# Generated by FakeRAM 2.0
VERSION 5.7 ;
BUSBITCHARS "[]" ;
PROPERTYDEFINITIONS
  MACRO width INTEGER ;
  MACRO depth INTEGER ;
  MACRO banks INTEGER ;
END PROPERTYDEFINITIONS
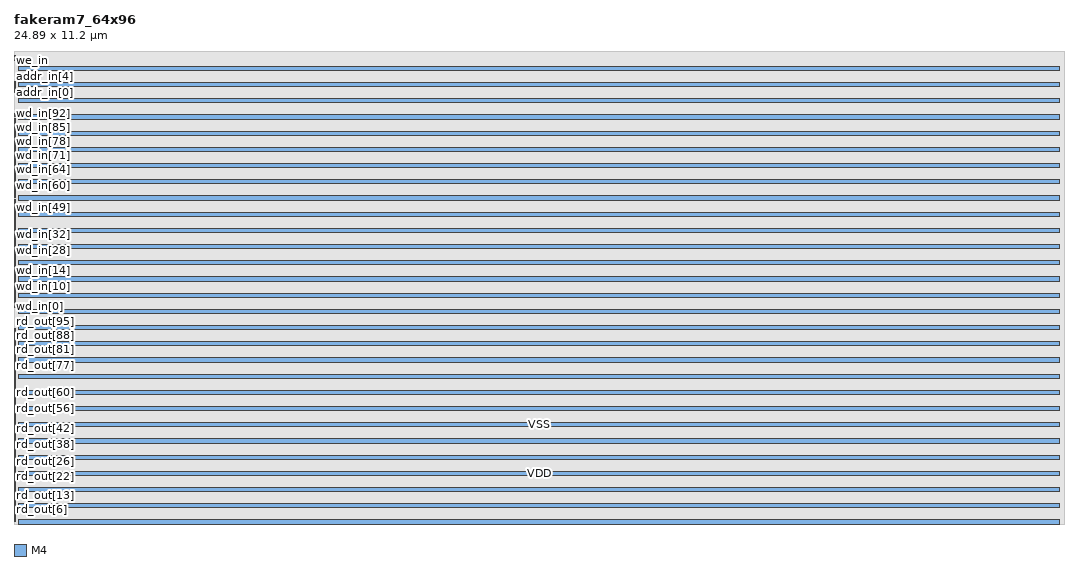
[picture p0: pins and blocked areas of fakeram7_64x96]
MACRO fakeram7_64x96
  PROPERTY width 96 ;
  PROPERTY depth 64 ;
  PROPERTY banks 2 ;
  FOREIGN fakeram7_64x96 0 0 ;
  SYMMETRY X Y R90 ;
  SIZE 24.8900 BY 11.2000 ;
  CLASS BLOCK ;
  PIN rd_out[0]
    DIRECTION OUTPUT ;
    USE SIGNAL ;
    PORT
      LAYER M4 ;
      RECT 0.00000 0.04800 0.03600 0.07200 ;
    END
  END rd_out[0]
  PIN rd_out[1]
    DIRECTION OUTPUT ;
    USE SIGNAL ;
    PORT
      LAYER M4 ;
      RECT 0.00000 0.09600 0.03600 0.12000 ;
    END
  END rd_out[1]
  PIN rd_out[2]
    DIRECTION OUTPUT ;
    USE SIGNAL ;
    PORT
      LAYER M4 ;
      RECT 0.00000 0.14400 0.03600 0.16800 ;
    END
  END rd_out[2]
  PIN rd_out[3]
    DIRECTION OUTPUT ;
    USE SIGNAL ;
    PORT
      LAYER M4 ;
      RECT 0.00000 0.19200 0.03600 0.21600 ;
    END
  END rd_out[3]
  PIN rd_out[4]
    DIRECTION OUTPUT ;
    USE SIGNAL ;
    PORT
      LAYER M4 ;
      RECT 0.00000 0.24000 0.03600 0.26400 ;
    END
  END rd_out[4]
  PIN rd_out[5]
    DIRECTION OUTPUT ;
    USE SIGNAL ;
    PORT
      LAYER M4 ;
      RECT 0.00000 0.28800 0.03600 0.31200 ;
    END
  END rd_out[5]
  PIN rd_out[6]
    DIRECTION OUTPUT ;
    USE SIGNAL ;
    PORT
      LAYER M4 ;
      RECT 0.00000 0.33600 0.03600 0.36000 ;
    END
  END rd_out[6]
  PIN rd_out[7]
    DIRECTION OUTPUT ;
    USE SIGNAL ;
    PORT
      LAYER M4 ;
      RECT 0.00000 0.38400 0.03600 0.40800 ;
    END
  END rd_out[7]
  PIN rd_out[8]
    DIRECTION OUTPUT ;
    USE SIGNAL ;
    PORT
      LAYER M4 ;
      RECT 0.00000 0.43200 0.03600 0.45600 ;
    END
  END rd_out[8]
  PIN rd_out[9]
    DIRECTION OUTPUT ;
    USE SIGNAL ;
    PORT
      LAYER M4 ;
      RECT 0.00000 0.48000 0.03600 0.50400 ;
    END
  END rd_out[9]
  PIN rd_out[10]
    DIRECTION OUTPUT ;
    USE SIGNAL ;
    PORT
      LAYER M4 ;
      RECT 0.00000 0.52800 0.03600 0.55200 ;
    END
  END rd_out[10]
  PIN rd_out[11]
    DIRECTION OUTPUT ;
    USE SIGNAL ;
    PORT
      LAYER M4 ;
      RECT 0.00000 0.57600 0.03600 0.60000 ;
    END
  END rd_out[11]
  PIN rd_out[12]
    DIRECTION OUTPUT ;
    USE SIGNAL ;
    PORT
      LAYER M4 ;
      RECT 0.00000 0.62400 0.03600 0.64800 ;
    END
  END rd_out[12]
  PIN rd_out[13]
    DIRECTION OUTPUT ;
    USE SIGNAL ;
    PORT
      LAYER M4 ;
      RECT 0.00000 0.67200 0.03600 0.69600 ;
    END
  END rd_out[13]
  PIN rd_out[14]
    DIRECTION OUTPUT ;
    USE SIGNAL ;
    PORT
      LAYER M4 ;
      RECT 0.00000 0.72000 0.03600 0.74400 ;
    END
  END rd_out[14]
  PIN rd_out[15]
    DIRECTION OUTPUT ;
    USE SIGNAL ;
    PORT
      LAYER M4 ;
      RECT 0.00000 0.76800 0.03600 0.79200 ;
    END
  END rd_out[15]
  PIN rd_out[16]
    DIRECTION OUTPUT ;
    USE SIGNAL ;
    PORT
      LAYER M4 ;
      RECT 0.00000 0.81600 0.03600 0.84000 ;
    END
  END rd_out[16]
  PIN rd_out[17]
    DIRECTION OUTPUT ;
    USE SIGNAL ;
    PORT
      LAYER M4 ;
      RECT 0.00000 0.86400 0.03600 0.88800 ;
    END
  END rd_out[17]
  PIN rd_out[18]
    DIRECTION OUTPUT ;
    USE SIGNAL ;
    PORT
      LAYER M4 ;
      RECT 0.00000 0.91200 0.03600 0.93600 ;
    END
  END rd_out[18]
  PIN rd_out[19]
    DIRECTION OUTPUT ;
    USE SIGNAL ;
    PORT
      LAYER M4 ;
      RECT 0.00000 0.96000 0.03600 0.98400 ;
    END
  END rd_out[19]
  PIN rd_out[20]
    DIRECTION OUTPUT ;
    USE SIGNAL ;
    PORT
      LAYER M4 ;
      RECT 0.00000 1.00800 0.03600 1.03200 ;
    END
  END rd_out[20]
  PIN rd_out[21]
    DIRECTION OUTPUT ;
    USE SIGNAL ;
    PORT
      LAYER M4 ;
      RECT 0.00000 1.05600 0.03600 1.08000 ;
    END
  END rd_out[21]
  PIN rd_out[22]
    DIRECTION OUTPUT ;
    USE SIGNAL ;
    PORT
      LAYER M4 ;
      RECT 0.00000 1.10400 0.03600 1.12800 ;
    END
  END rd_out[22]
  PIN rd_out[23]
    DIRECTION OUTPUT ;
    USE SIGNAL ;
    PORT
      LAYER M4 ;
      RECT 0.00000 1.15200 0.03600 1.17600 ;
    END
  END rd_out[23]
  PIN rd_out[24]
    DIRECTION OUTPUT ;
    USE SIGNAL ;
    PORT
      LAYER M4 ;
      RECT 0.00000 1.20000 0.03600 1.22400 ;
    END
  END rd_out[24]
  PIN rd_out[25]
    DIRECTION OUTPUT ;
    USE SIGNAL ;
    PORT
      LAYER M4 ;
      RECT 0.00000 1.24800 0.03600 1.27200 ;
    END
  END rd_out[25]
  PIN rd_out[26]
    DIRECTION OUTPUT ;
    USE SIGNAL ;
    PORT
      LAYER M4 ;
      RECT 0.00000 1.29600 0.03600 1.32000 ;
    END
  END rd_out[26]
  PIN rd_out[27]
    DIRECTION OUTPUT ;
    USE SIGNAL ;
    PORT
      LAYER M4 ;
      RECT 0.00000 1.34400 0.03600 1.36800 ;
    END
  END rd_out[27]
  PIN rd_out[28]
    DIRECTION OUTPUT ;
    USE SIGNAL ;
    PORT
      LAYER M4 ;
      RECT 0.00000 1.39200 0.03600 1.41600 ;
    END
  END rd_out[28]
  PIN rd_out[29]
    DIRECTION OUTPUT ;
    USE SIGNAL ;
    PORT
      LAYER M4 ;
      RECT 0.00000 1.44000 0.03600 1.46400 ;
    END
  END rd_out[29]
  PIN rd_out[30]
    DIRECTION OUTPUT ;
    USE SIGNAL ;
    PORT
      LAYER M4 ;
      RECT 0.00000 1.48800 0.03600 1.51200 ;
    END
  END rd_out[30]
  PIN rd_out[31]
    DIRECTION OUTPUT ;
    USE SIGNAL ;
    PORT
      LAYER M4 ;
      RECT 0.00000 1.53600 0.03600 1.56000 ;
    END
  END rd_out[31]
  PIN rd_out[32]
    DIRECTION OUTPUT ;
    USE SIGNAL ;
    PORT
      LAYER M4 ;
      RECT 0.00000 1.58400 0.03600 1.60800 ;
    END
  END rd_out[32]
  PIN rd_out[33]
    DIRECTION OUTPUT ;
    USE SIGNAL ;
    PORT
      LAYER M4 ;
      RECT 0.00000 1.63200 0.03600 1.65600 ;
    END
  END rd_out[33]
  PIN rd_out[34]
    DIRECTION OUTPUT ;
    USE SIGNAL ;
    PORT
      LAYER M4 ;
      RECT 0.00000 1.68000 0.03600 1.70400 ;
    END
  END rd_out[34]
  PIN rd_out[35]
    DIRECTION OUTPUT ;
    USE SIGNAL ;
    PORT
      LAYER M4 ;
      RECT 0.00000 1.72800 0.03600 1.75200 ;
    END
  END rd_out[35]
  PIN rd_out[36]
    DIRECTION OUTPUT ;
    USE SIGNAL ;
    PORT
      LAYER M4 ;
      RECT 0.00000 1.77600 0.03600 1.80000 ;
    END
  END rd_out[36]
  PIN rd_out[37]
    DIRECTION OUTPUT ;
    USE SIGNAL ;
    PORT
      LAYER M4 ;
      RECT 0.00000 1.82400 0.03600 1.84800 ;
    END
  END rd_out[37]
  PIN rd_out[38]
    DIRECTION OUTPUT ;
    USE SIGNAL ;
    PORT
      LAYER M4 ;
      RECT 0.00000 1.87200 0.03600 1.89600 ;
    END
  END rd_out[38]
  PIN rd_out[39]
    DIRECTION OUTPUT ;
    USE SIGNAL ;
    PORT
      LAYER M4 ;
      RECT 0.00000 1.92000 0.03600 1.94400 ;
    END
  END rd_out[39]
  PIN rd_out[40]
    DIRECTION OUTPUT ;
    USE SIGNAL ;
    PORT
      LAYER M4 ;
      RECT 0.00000 1.96800 0.03600 1.99200 ;
    END
  END rd_out[40]
  PIN rd_out[41]
    DIRECTION OUTPUT ;
    USE SIGNAL ;
    PORT
      LAYER M4 ;
      RECT 0.00000 2.01600 0.03600 2.04000 ;
    END
  END rd_out[41]
  PIN rd_out[42]
    DIRECTION OUTPUT ;
    USE SIGNAL ;
    PORT
      LAYER M4 ;
      RECT 0.00000 2.06400 0.03600 2.08800 ;
    END
  END rd_out[42]
  PIN rd_out[43]
    DIRECTION OUTPUT ;
    USE SIGNAL ;
    PORT
      LAYER M4 ;
      RECT 0.00000 2.11200 0.03600 2.13600 ;
    END
  END rd_out[43]
  PIN rd_out[44]
    DIRECTION OUTPUT ;
    USE SIGNAL ;
    PORT
      LAYER M4 ;
      RECT 0.00000 2.16000 0.03600 2.18400 ;
    END
  END rd_out[44]
  PIN rd_out[45]
    DIRECTION OUTPUT ;
    USE SIGNAL ;
    PORT
      LAYER M4 ;
      RECT 0.00000 2.20800 0.03600 2.23200 ;
    END
  END rd_out[45]
  PIN rd_out[46]
    DIRECTION OUTPUT ;
    USE SIGNAL ;
    PORT
      LAYER M4 ;
      RECT 0.00000 2.25600 0.03600 2.28000 ;
    END
  END rd_out[46]
  PIN rd_out[47]
    DIRECTION OUTPUT ;
    USE SIGNAL ;
    PORT
      LAYER M4 ;
      RECT 0.00000 2.30400 0.03600 2.32800 ;
    END
  END rd_out[47]
  PIN rd_out[48]
    DIRECTION OUTPUT ;
    USE SIGNAL ;
    PORT
      LAYER M4 ;
      RECT 0.00000 2.35200 0.03600 2.37600 ;
    END
  END rd_out[48]
  PIN rd_out[49]
    DIRECTION OUTPUT ;
    USE SIGNAL ;
    PORT
      LAYER M4 ;
      RECT 0.00000 2.40000 0.03600 2.42400 ;
    END
  END rd_out[49]
  PIN rd_out[50]
    DIRECTION OUTPUT ;
    USE SIGNAL ;
    PORT
      LAYER M4 ;
      RECT 0.00000 2.44800 0.03600 2.47200 ;
    END
  END rd_out[50]
  PIN rd_out[51]
    DIRECTION OUTPUT ;
    USE SIGNAL ;
    PORT
      LAYER M4 ;
      RECT 0.00000 2.49600 0.03600 2.52000 ;
    END
  END rd_out[51]
  PIN rd_out[52]
    DIRECTION OUTPUT ;
    USE SIGNAL ;
    PORT
      LAYER M4 ;
      RECT 0.00000 2.54400 0.03600 2.56800 ;
    END
  END rd_out[52]
  PIN rd_out[53]
    DIRECTION OUTPUT ;
    USE SIGNAL ;
    PORT
      LAYER M4 ;
      RECT 0.00000 2.59200 0.03600 2.61600 ;
    END
  END rd_out[53]
  PIN rd_out[54]
    DIRECTION OUTPUT ;
    USE SIGNAL ;
    PORT
      LAYER M4 ;
      RECT 0.00000 2.64000 0.03600 2.66400 ;
    END
  END rd_out[54]
  PIN rd_out[55]
    DIRECTION OUTPUT ;
    USE SIGNAL ;
    PORT
      LAYER M4 ;
      RECT 0.00000 2.68800 0.03600 2.71200 ;
    END
  END rd_out[55]
  PIN rd_out[56]
    DIRECTION OUTPUT ;
    USE SIGNAL ;
    PORT
      LAYER M4 ;
      RECT 0.00000 2.73600 0.03600 2.76000 ;
    END
  END rd_out[56]
  PIN rd_out[57]
    DIRECTION OUTPUT ;
    USE SIGNAL ;
    PORT
      LAYER M4 ;
      RECT 0.00000 2.78400 0.03600 2.80800 ;
    END
  END rd_out[57]
  PIN rd_out[58]
    DIRECTION OUTPUT ;
    USE SIGNAL ;
    PORT
      LAYER M4 ;
      RECT 0.00000 2.83200 0.03600 2.85600 ;
    END
  END rd_out[58]
  PIN rd_out[59]
    DIRECTION OUTPUT ;
    USE SIGNAL ;
    PORT
      LAYER M4 ;
      RECT 0.00000 2.88000 0.03600 2.90400 ;
    END
  END rd_out[59]
  PIN rd_out[60]
    DIRECTION OUTPUT ;
    USE SIGNAL ;
    PORT
      LAYER M4 ;
      RECT 0.00000 2.92800 0.03600 2.95200 ;
    END
  END rd_out[60]
  PIN rd_out[61]
    DIRECTION OUTPUT ;
    USE SIGNAL ;
    PORT
      LAYER M4 ;
      RECT 0.00000 2.97600 0.03600 3.00000 ;
    END
  END rd_out[61]
  PIN rd_out[62]
    DIRECTION OUTPUT ;
    USE SIGNAL ;
    PORT
      LAYER M4 ;
      RECT 0.00000 3.02400 0.03600 3.04800 ;
    END
  END rd_out[62]
  PIN rd_out[63]
    DIRECTION OUTPUT ;
    USE SIGNAL ;
    PORT
      LAYER M4 ;
      RECT 0.00000 3.07200 0.03600 3.09600 ;
    END
  END rd_out[63]
  PIN rd_out[64]
    DIRECTION OUTPUT ;
    USE SIGNAL ;
    PORT
      LAYER M4 ;
      RECT 0.00000 3.12000 0.03600 3.14400 ;
    END
  END rd_out[64]
  PIN rd_out[65]
    DIRECTION OUTPUT ;
    USE SIGNAL ;
    PORT
      LAYER M4 ;
      RECT 0.00000 3.16800 0.03600 3.19200 ;
    END
  END rd_out[65]
  PIN rd_out[66]
    DIRECTION OUTPUT ;
    USE SIGNAL ;
    PORT
      LAYER M4 ;
      RECT 0.00000 3.21600 0.03600 3.24000 ;
    END
  END rd_out[66]
  PIN rd_out[67]
    DIRECTION OUTPUT ;
    USE SIGNAL ;
    PORT
      LAYER M4 ;
      RECT 0.00000 3.26400 0.03600 3.28800 ;
    END
  END rd_out[67]
  PIN rd_out[68]
    DIRECTION OUTPUT ;
    USE SIGNAL ;
    PORT
      LAYER M4 ;
      RECT 0.00000 3.31200 0.03600 3.33600 ;
    END
  END rd_out[68]
  PIN rd_out[69]
    DIRECTION OUTPUT ;
    USE SIGNAL ;
    PORT
      LAYER M4 ;
      RECT 0.00000 3.36000 0.03600 3.38400 ;
    END
  END rd_out[69]
  PIN rd_out[70]
    DIRECTION OUTPUT ;
    USE SIGNAL ;
    PORT
      LAYER M4 ;
      RECT 0.00000 3.40800 0.03600 3.43200 ;
    END
  END rd_out[70]
  PIN rd_out[71]
    DIRECTION OUTPUT ;
    USE SIGNAL ;
    PORT
      LAYER M4 ;
      RECT 0.00000 3.45600 0.03600 3.48000 ;
    END
  END rd_out[71]
  PIN rd_out[72]
    DIRECTION OUTPUT ;
    USE SIGNAL ;
    PORT
      LAYER M4 ;
      RECT 0.00000 3.50400 0.03600 3.52800 ;
    END
  END rd_out[72]
  PIN rd_out[73]
    DIRECTION OUTPUT ;
    USE SIGNAL ;
    PORT
      LAYER M4 ;
      RECT 0.00000 3.55200 0.03600 3.57600 ;
    END
  END rd_out[73]
  PIN rd_out[74]
    DIRECTION OUTPUT ;
    USE SIGNAL ;
    PORT
      LAYER M4 ;
      RECT 0.00000 3.60000 0.03600 3.62400 ;
    END
  END rd_out[74]
  PIN rd_out[75]
    DIRECTION OUTPUT ;
    USE SIGNAL ;
    PORT
      LAYER M4 ;
      RECT 0.00000 3.64800 0.03600 3.67200 ;
    END
  END rd_out[75]
  PIN rd_out[76]
    DIRECTION OUTPUT ;
    USE SIGNAL ;
    PORT
      LAYER M4 ;
      RECT 0.00000 3.69600 0.03600 3.72000 ;
    END
  END rd_out[76]
  PIN rd_out[77]
    DIRECTION OUTPUT ;
    USE SIGNAL ;
    PORT
      LAYER M4 ;
      RECT 0.00000 3.74400 0.03600 3.76800 ;
    END
  END rd_out[77]
  PIN rd_out[78]
    DIRECTION OUTPUT ;
    USE SIGNAL ;
    PORT
      LAYER M4 ;
      RECT 0.00000 3.79200 0.03600 3.81600 ;
    END
  END rd_out[78]
  PIN rd_out[79]
    DIRECTION OUTPUT ;
    USE SIGNAL ;
    PORT
      LAYER M4 ;
      RECT 0.00000 3.84000 0.03600 3.86400 ;
    END
  END rd_out[79]
  PIN rd_out[80]
    DIRECTION OUTPUT ;
    USE SIGNAL ;
    PORT
      LAYER M4 ;
      RECT 0.00000 3.88800 0.03600 3.91200 ;
    END
  END rd_out[80]
  PIN rd_out[81]
    DIRECTION OUTPUT ;
    USE SIGNAL ;
    PORT
      LAYER M4 ;
      RECT 0.00000 3.93600 0.03600 3.96000 ;
    END
  END rd_out[81]
  PIN rd_out[82]
    DIRECTION OUTPUT ;
    USE SIGNAL ;
    PORT
      LAYER M4 ;
      RECT 0.00000 3.98400 0.03600 4.00800 ;
    END
  END rd_out[82]
  PIN rd_out[83]
    DIRECTION OUTPUT ;
    USE SIGNAL ;
    PORT
      LAYER M4 ;
      RECT 0.00000 4.03200 0.03600 4.05600 ;
    END
  END rd_out[83]
  PIN rd_out[84]
    DIRECTION OUTPUT ;
    USE SIGNAL ;
    PORT
      LAYER M4 ;
      RECT 0.00000 4.08000 0.03600 4.10400 ;
    END
  END rd_out[84]
  PIN rd_out[85]
    DIRECTION OUTPUT ;
    USE SIGNAL ;
    PORT
      LAYER M4 ;
      RECT 0.00000 4.12800 0.03600 4.15200 ;
    END
  END rd_out[85]
  PIN rd_out[86]
    DIRECTION OUTPUT ;
    USE SIGNAL ;
    PORT
      LAYER M4 ;
      RECT 0.00000 4.17600 0.03600 4.20000 ;
    END
  END rd_out[86]
  PIN rd_out[87]
    DIRECTION OUTPUT ;
    USE SIGNAL ;
    PORT
      LAYER M4 ;
      RECT 0.00000 4.22400 0.03600 4.24800 ;
    END
  END rd_out[87]
  PIN rd_out[88]
    DIRECTION OUTPUT ;
    USE SIGNAL ;
    PORT
      LAYER M4 ;
      RECT 0.00000 4.27200 0.03600 4.29600 ;
    END
  END rd_out[88]
  PIN rd_out[89]
    DIRECTION OUTPUT ;
    USE SIGNAL ;
    PORT
      LAYER M4 ;
      RECT 0.00000 4.32000 0.03600 4.34400 ;
    END
  END rd_out[89]
  PIN rd_out[90]
    DIRECTION OUTPUT ;
    USE SIGNAL ;
    PORT
      LAYER M4 ;
      RECT 0.00000 4.36800 0.03600 4.39200 ;
    END
  END rd_out[90]
  PIN rd_out[91]
    DIRECTION OUTPUT ;
    USE SIGNAL ;
    PORT
      LAYER M4 ;
      RECT 0.00000 4.41600 0.03600 4.44000 ;
    END
  END rd_out[91]
  PIN rd_out[92]
    DIRECTION OUTPUT ;
    USE SIGNAL ;
    PORT
      LAYER M4 ;
      RECT 0.00000 4.46400 0.03600 4.48800 ;
    END
  END rd_out[92]
  PIN rd_out[93]
    DIRECTION OUTPUT ;
    USE SIGNAL ;
    PORT
      LAYER M4 ;
      RECT 0.00000 4.51200 0.03600 4.53600 ;
    END
  END rd_out[93]
  PIN rd_out[94]
    DIRECTION OUTPUT ;
    USE SIGNAL ;
    PORT
      LAYER M4 ;
      RECT 0.00000 4.56000 0.03600 4.58400 ;
    END
  END rd_out[94]
  PIN rd_out[95]
    DIRECTION OUTPUT ;
    USE SIGNAL ;
    PORT
      LAYER M4 ;
      RECT 0.00000 4.60800 0.03600 4.63200 ;
    END
  END rd_out[95]
  PIN wd_in[0]
    DIRECTION INPUT ;
    USE SIGNAL ;
    PORT
      LAYER M4 ;
      RECT 0.00000 5.13600 0.03600 5.16000 ;
    END
  END wd_in[0]
  PIN wd_in[1]
    DIRECTION INPUT ;
    USE SIGNAL ;
    PORT
      LAYER M4 ;
      RECT 0.00000 5.18400 0.03600 5.20800 ;
    END
  END wd_in[1]
  PIN wd_in[2]
    DIRECTION INPUT ;
    USE SIGNAL ;
    PORT
      LAYER M4 ;
      RECT 0.00000 5.23200 0.03600 5.25600 ;
    END
  END wd_in[2]
  PIN wd_in[3]
    DIRECTION INPUT ;
    USE SIGNAL ;
    PORT
      LAYER M4 ;
      RECT 0.00000 5.28000 0.03600 5.30400 ;
    END
  END wd_in[3]
  PIN wd_in[4]
    DIRECTION INPUT ;
    USE SIGNAL ;
    PORT
      LAYER M4 ;
      RECT 0.00000 5.32800 0.03600 5.35200 ;
    END
  END wd_in[4]
  PIN wd_in[5]
    DIRECTION INPUT ;
    USE SIGNAL ;
    PORT
      LAYER M4 ;
      RECT 0.00000 5.37600 0.03600 5.40000 ;
    END
  END wd_in[5]
  PIN wd_in[6]
    DIRECTION INPUT ;
    USE SIGNAL ;
    PORT
      LAYER M4 ;
      RECT 0.00000 5.42400 0.03600 5.44800 ;
    END
  END wd_in[6]
  PIN wd_in[7]
    DIRECTION INPUT ;
    USE SIGNAL ;
    PORT
      LAYER M4 ;
      RECT 0.00000 5.47200 0.03600 5.49600 ;
    END
  END wd_in[7]
  PIN wd_in[8]
    DIRECTION INPUT ;
    USE SIGNAL ;
    PORT
      LAYER M4 ;
      RECT 0.00000 5.52000 0.03600 5.54400 ;
    END
  END wd_in[8]
  PIN wd_in[9]
    DIRECTION INPUT ;
    USE SIGNAL ;
    PORT
      LAYER M4 ;
      RECT 0.00000 5.56800 0.03600 5.59200 ;
    END
  END wd_in[9]
  PIN wd_in[10]
    DIRECTION INPUT ;
    USE SIGNAL ;
    PORT
      LAYER M4 ;
      RECT 0.00000 5.61600 0.03600 5.64000 ;
    END
  END wd_in[10]
  PIN wd_in[11]
    DIRECTION INPUT ;
    USE SIGNAL ;
    PORT
      LAYER M4 ;
      RECT 0.00000 5.66400 0.03600 5.68800 ;
    END
  END wd_in[11]
  PIN wd_in[12]
    DIRECTION INPUT ;
    USE SIGNAL ;
    PORT
      LAYER M4 ;
      RECT 0.00000 5.71200 0.03600 5.73600 ;
    END
  END wd_in[12]
  PIN wd_in[13]
    DIRECTION INPUT ;
    USE SIGNAL ;
    PORT
      LAYER M4 ;
      RECT 0.00000 5.76000 0.03600 5.78400 ;
    END
  END wd_in[13]
  PIN wd_in[14]
    DIRECTION INPUT ;
    USE SIGNAL ;
    PORT
      LAYER M4 ;
      RECT 0.00000 5.80800 0.03600 5.83200 ;
    END
  END wd_in[14]
  PIN wd_in[15]
    DIRECTION INPUT ;
    USE SIGNAL ;
    PORT
      LAYER M4 ;
      RECT 0.00000 5.85600 0.03600 5.88000 ;
    END
  END wd_in[15]
  PIN wd_in[16]
    DIRECTION INPUT ;
    USE SIGNAL ;
    PORT
      LAYER M4 ;
      RECT 0.00000 5.90400 0.03600 5.92800 ;
    END
  END wd_in[16]
  PIN wd_in[17]
    DIRECTION INPUT ;
    USE SIGNAL ;
    PORT
      LAYER M4 ;
      RECT 0.00000 5.95200 0.03600 5.97600 ;
    END
  END wd_in[17]
  PIN wd_in[18]
    DIRECTION INPUT ;
    USE SIGNAL ;
    PORT
      LAYER M4 ;
      RECT 0.00000 6.00000 0.03600 6.02400 ;
    END
  END wd_in[18]
  PIN wd_in[19]
    DIRECTION INPUT ;
    USE SIGNAL ;
    PORT
      LAYER M4 ;
      RECT 0.00000 6.04800 0.03600 6.07200 ;
    END
  END wd_in[19]
  PIN wd_in[20]
    DIRECTION INPUT ;
    USE SIGNAL ;
    PORT
      LAYER M4 ;
      RECT 0.00000 6.09600 0.03600 6.12000 ;
    END
  END wd_in[20]
  PIN wd_in[21]
    DIRECTION INPUT ;
    USE SIGNAL ;
    PORT
      LAYER M4 ;
      RECT 0.00000 6.14400 0.03600 6.16800 ;
    END
  END wd_in[21]
  PIN wd_in[22]
    DIRECTION INPUT ;
    USE SIGNAL ;
    PORT
      LAYER M4 ;
      RECT 0.00000 6.19200 0.03600 6.21600 ;
    END
  END wd_in[22]
  PIN wd_in[23]
    DIRECTION INPUT ;
    USE SIGNAL ;
    PORT
      LAYER M4 ;
      RECT 0.00000 6.24000 0.03600 6.26400 ;
    END
  END wd_in[23]
  PIN wd_in[24]
    DIRECTION INPUT ;
    USE SIGNAL ;
    PORT
      LAYER M4 ;
      RECT 0.00000 6.28800 0.03600 6.31200 ;
    END
  END wd_in[24]
  PIN wd_in[25]
    DIRECTION INPUT ;
    USE SIGNAL ;
    PORT
      LAYER M4 ;
      RECT 0.00000 6.33600 0.03600 6.36000 ;
    END
  END wd_in[25]
  PIN wd_in[26]
    DIRECTION INPUT ;
    USE SIGNAL ;
    PORT
      LAYER M4 ;
      RECT 0.00000 6.38400 0.03600 6.40800 ;
    END
  END wd_in[26]
  PIN wd_in[27]
    DIRECTION INPUT ;
    USE SIGNAL ;
    PORT
      LAYER M4 ;
      RECT 0.00000 6.43200 0.03600 6.45600 ;
    END
  END wd_in[27]
  PIN wd_in[28]
    DIRECTION INPUT ;
    USE SIGNAL ;
    PORT
      LAYER M4 ;
      RECT 0.00000 6.48000 0.03600 6.50400 ;
    END
  END wd_in[28]
  PIN wd_in[29]
    DIRECTION INPUT ;
    USE SIGNAL ;
    PORT
      LAYER M4 ;
      RECT 0.00000 6.52800 0.03600 6.55200 ;
    END
  END wd_in[29]
  PIN wd_in[30]
    DIRECTION INPUT ;
    USE SIGNAL ;
    PORT
      LAYER M4 ;
      RECT 0.00000 6.57600 0.03600 6.60000 ;
    END
  END wd_in[30]
  PIN wd_in[31]
    DIRECTION INPUT ;
    USE SIGNAL ;
    PORT
      LAYER M4 ;
      RECT 0.00000 6.62400 0.03600 6.64800 ;
    END
  END wd_in[31]
  PIN wd_in[32]
    DIRECTION INPUT ;
    USE SIGNAL ;
    PORT
      LAYER M4 ;
      RECT 0.00000 6.67200 0.03600 6.69600 ;
    END
  END wd_in[32]
  PIN wd_in[33]
    DIRECTION INPUT ;
    USE SIGNAL ;
    PORT
      LAYER M4 ;
      RECT 0.00000 6.72000 0.03600 6.74400 ;
    END
  END wd_in[33]
  PIN wd_in[34]
    DIRECTION INPUT ;
    USE SIGNAL ;
    PORT
      LAYER M4 ;
      RECT 0.00000 6.76800 0.03600 6.79200 ;
    END
  END wd_in[34]
  PIN wd_in[35]
    DIRECTION INPUT ;
    USE SIGNAL ;
    PORT
      LAYER M4 ;
      RECT 0.00000 6.81600 0.03600 6.84000 ;
    END
  END wd_in[35]
  PIN wd_in[36]
    DIRECTION INPUT ;
    USE SIGNAL ;
    PORT
      LAYER M4 ;
      RECT 0.00000 6.86400 0.03600 6.88800 ;
    END
  END wd_in[36]
  PIN wd_in[37]
    DIRECTION INPUT ;
    USE SIGNAL ;
    PORT
      LAYER M4 ;
      RECT 0.00000 6.91200 0.03600 6.93600 ;
    END
  END wd_in[37]
  PIN wd_in[38]
    DIRECTION INPUT ;
    USE SIGNAL ;
    PORT
      LAYER M4 ;
      RECT 0.00000 6.96000 0.03600 6.98400 ;
    END
  END wd_in[38]
  PIN wd_in[39]
    DIRECTION INPUT ;
    USE SIGNAL ;
    PORT
      LAYER M4 ;
      RECT 0.00000 7.00800 0.03600 7.03200 ;
    END
  END wd_in[39]
  PIN wd_in[40]
    DIRECTION INPUT ;
    USE SIGNAL ;
    PORT
      LAYER M4 ;
      RECT 0.00000 7.05600 0.03600 7.08000 ;
    END
  END wd_in[40]
  PIN wd_in[41]
    DIRECTION INPUT ;
    USE SIGNAL ;
    PORT
      LAYER M4 ;
      RECT 0.00000 7.10400 0.03600 7.12800 ;
    END
  END wd_in[41]
  PIN wd_in[42]
    DIRECTION INPUT ;
    USE SIGNAL ;
    PORT
      LAYER M4 ;
      RECT 0.00000 7.15200 0.03600 7.17600 ;
    END
  END wd_in[42]
  PIN wd_in[43]
    DIRECTION INPUT ;
    USE SIGNAL ;
    PORT
      LAYER M4 ;
      RECT 0.00000 7.20000 0.03600 7.22400 ;
    END
  END wd_in[43]
  PIN wd_in[44]
    DIRECTION INPUT ;
    USE SIGNAL ;
    PORT
      LAYER M4 ;
      RECT 0.00000 7.24800 0.03600 7.27200 ;
    END
  END wd_in[44]
  PIN wd_in[45]
    DIRECTION INPUT ;
    USE SIGNAL ;
    PORT
      LAYER M4 ;
      RECT 0.00000 7.29600 0.03600 7.32000 ;
    END
  END wd_in[45]
  PIN wd_in[46]
    DIRECTION INPUT ;
    USE SIGNAL ;
    PORT
      LAYER M4 ;
      RECT 0.00000 7.34400 0.03600 7.36800 ;
    END
  END wd_in[46]
  PIN wd_in[47]
    DIRECTION INPUT ;
    USE SIGNAL ;
    PORT
      LAYER M4 ;
      RECT 0.00000 7.39200 0.03600 7.41600 ;
    END
  END wd_in[47]
  PIN wd_in[48]
    DIRECTION INPUT ;
    USE SIGNAL ;
    PORT
      LAYER M4 ;
      RECT 0.00000 7.44000 0.03600 7.46400 ;
    END
  END wd_in[48]
  PIN wd_in[49]
    DIRECTION INPUT ;
    USE SIGNAL ;
    PORT
      LAYER M4 ;
      RECT 0.00000 7.48800 0.03600 7.51200 ;
    END
  END wd_in[49]
  PIN wd_in[50]
    DIRECTION INPUT ;
    USE SIGNAL ;
    PORT
      LAYER M4 ;
      RECT 0.00000 7.53600 0.03600 7.56000 ;
    END
  END wd_in[50]
  PIN wd_in[51]
    DIRECTION INPUT ;
    USE SIGNAL ;
    PORT
      LAYER M4 ;
      RECT 0.00000 7.58400 0.03600 7.60800 ;
    END
  END wd_in[51]
  PIN wd_in[52]
    DIRECTION INPUT ;
    USE SIGNAL ;
    PORT
      LAYER M4 ;
      RECT 0.00000 7.63200 0.03600 7.65600 ;
    END
  END wd_in[52]
  PIN wd_in[53]
    DIRECTION INPUT ;
    USE SIGNAL ;
    PORT
      LAYER M4 ;
      RECT 0.00000 7.68000 0.03600 7.70400 ;
    END
  END wd_in[53]
  PIN wd_in[54]
    DIRECTION INPUT ;
    USE SIGNAL ;
    PORT
      LAYER M4 ;
      RECT 0.00000 7.72800 0.03600 7.75200 ;
    END
  END wd_in[54]
  PIN wd_in[55]
    DIRECTION INPUT ;
    USE SIGNAL ;
    PORT
      LAYER M4 ;
      RECT 0.00000 7.77600 0.03600 7.80000 ;
    END
  END wd_in[55]
  PIN wd_in[56]
    DIRECTION INPUT ;
    USE SIGNAL ;
    PORT
      LAYER M4 ;
      RECT 0.00000 7.82400 0.03600 7.84800 ;
    END
  END wd_in[56]
  PIN wd_in[57]
    DIRECTION INPUT ;
    USE SIGNAL ;
    PORT
      LAYER M4 ;
      RECT 0.00000 7.87200 0.03600 7.89600 ;
    END
  END wd_in[57]
  PIN wd_in[58]
    DIRECTION INPUT ;
    USE SIGNAL ;
    PORT
      LAYER M4 ;
      RECT 0.00000 7.92000 0.03600 7.94400 ;
    END
  END wd_in[58]
  PIN wd_in[59]
    DIRECTION INPUT ;
    USE SIGNAL ;
    PORT
      LAYER M4 ;
      RECT 0.00000 7.96800 0.03600 7.99200 ;
    END
  END wd_in[59]
  PIN wd_in[60]
    DIRECTION INPUT ;
    USE SIGNAL ;
    PORT
      LAYER M4 ;
      RECT 0.00000 8.01600 0.03600 8.04000 ;
    END
  END wd_in[60]
  PIN wd_in[61]
    DIRECTION INPUT ;
    USE SIGNAL ;
    PORT
      LAYER M4 ;
      RECT 0.00000 8.06400 0.03600 8.08800 ;
    END
  END wd_in[61]
  PIN wd_in[62]
    DIRECTION INPUT ;
    USE SIGNAL ;
    PORT
      LAYER M4 ;
      RECT 0.00000 8.11200 0.03600 8.13600 ;
    END
  END wd_in[62]
  PIN wd_in[63]
    DIRECTION INPUT ;
    USE SIGNAL ;
    PORT
      LAYER M4 ;
      RECT 0.00000 8.16000 0.03600 8.18400 ;
    END
  END wd_in[63]
  PIN wd_in[64]
    DIRECTION INPUT ;
    USE SIGNAL ;
    PORT
      LAYER M4 ;
      RECT 0.00000 8.20800 0.03600 8.23200 ;
    END
  END wd_in[64]
  PIN wd_in[65]
    DIRECTION INPUT ;
    USE SIGNAL ;
    PORT
      LAYER M4 ;
      RECT 0.00000 8.25600 0.03600 8.28000 ;
    END
  END wd_in[65]
  PIN wd_in[66]
    DIRECTION INPUT ;
    USE SIGNAL ;
    PORT
      LAYER M4 ;
      RECT 0.00000 8.30400 0.03600 8.32800 ;
    END
  END wd_in[66]
  PIN wd_in[67]
    DIRECTION INPUT ;
    USE SIGNAL ;
    PORT
      LAYER M4 ;
      RECT 0.00000 8.35200 0.03600 8.37600 ;
    END
  END wd_in[67]
  PIN wd_in[68]
    DIRECTION INPUT ;
    USE SIGNAL ;
    PORT
      LAYER M4 ;
      RECT 0.00000 8.40000 0.03600 8.42400 ;
    END
  END wd_in[68]
  PIN wd_in[69]
    DIRECTION INPUT ;
    USE SIGNAL ;
    PORT
      LAYER M4 ;
      RECT 0.00000 8.44800 0.03600 8.47200 ;
    END
  END wd_in[69]
  PIN wd_in[70]
    DIRECTION INPUT ;
    USE SIGNAL ;
    PORT
      LAYER M4 ;
      RECT 0.00000 8.49600 0.03600 8.52000 ;
    END
  END wd_in[70]
  PIN wd_in[71]
    DIRECTION INPUT ;
    USE SIGNAL ;
    PORT
      LAYER M4 ;
      RECT 0.00000 8.54400 0.03600 8.56800 ;
    END
  END wd_in[71]
  PIN wd_in[72]
    DIRECTION INPUT ;
    USE SIGNAL ;
    PORT
      LAYER M4 ;
      RECT 0.00000 8.59200 0.03600 8.61600 ;
    END
  END wd_in[72]
  PIN wd_in[73]
    DIRECTION INPUT ;
    USE SIGNAL ;
    PORT
      LAYER M4 ;
      RECT 0.00000 8.64000 0.03600 8.66400 ;
    END
  END wd_in[73]
  PIN wd_in[74]
    DIRECTION INPUT ;
    USE SIGNAL ;
    PORT
      LAYER M4 ;
      RECT 0.00000 8.68800 0.03600 8.71200 ;
    END
  END wd_in[74]
  PIN wd_in[75]
    DIRECTION INPUT ;
    USE SIGNAL ;
    PORT
      LAYER M4 ;
      RECT 0.00000 8.73600 0.03600 8.76000 ;
    END
  END wd_in[75]
  PIN wd_in[76]
    DIRECTION INPUT ;
    USE SIGNAL ;
    PORT
      LAYER M4 ;
      RECT 0.00000 8.78400 0.03600 8.80800 ;
    END
  END wd_in[76]
  PIN wd_in[77]
    DIRECTION INPUT ;
    USE SIGNAL ;
    PORT
      LAYER M4 ;
      RECT 0.00000 8.83200 0.03600 8.85600 ;
    END
  END wd_in[77]
  PIN wd_in[78]
    DIRECTION INPUT ;
    USE SIGNAL ;
    PORT
      LAYER M4 ;
      RECT 0.00000 8.88000 0.03600 8.90400 ;
    END
  END wd_in[78]
  PIN wd_in[79]
    DIRECTION INPUT ;
    USE SIGNAL ;
    PORT
      LAYER M4 ;
      RECT 0.00000 8.92800 0.03600 8.95200 ;
    END
  END wd_in[79]
  PIN wd_in[80]
    DIRECTION INPUT ;
    USE SIGNAL ;
    PORT
      LAYER M4 ;
      RECT 0.00000 8.97600 0.03600 9.00000 ;
    END
  END wd_in[80]
  PIN wd_in[81]
    DIRECTION INPUT ;
    USE SIGNAL ;
    PORT
      LAYER M4 ;
      RECT 0.00000 9.02400 0.03600 9.04800 ;
    END
  END wd_in[81]
  PIN wd_in[82]
    DIRECTION INPUT ;
    USE SIGNAL ;
    PORT
      LAYER M4 ;
      RECT 0.00000 9.07200 0.03600 9.09600 ;
    END
  END wd_in[82]
  PIN wd_in[83]
    DIRECTION INPUT ;
    USE SIGNAL ;
    PORT
      LAYER M4 ;
      RECT 0.00000 9.12000 0.03600 9.14400 ;
    END
  END wd_in[83]
  PIN wd_in[84]
    DIRECTION INPUT ;
    USE SIGNAL ;
    PORT
      LAYER M4 ;
      RECT 0.00000 9.16800 0.03600 9.19200 ;
    END
  END wd_in[84]
  PIN wd_in[85]
    DIRECTION INPUT ;
    USE SIGNAL ;
    PORT
      LAYER M4 ;
      RECT 0.00000 9.21600 0.03600 9.24000 ;
    END
  END wd_in[85]
  PIN wd_in[86]
    DIRECTION INPUT ;
    USE SIGNAL ;
    PORT
      LAYER M4 ;
      RECT 0.00000 9.26400 0.03600 9.28800 ;
    END
  END wd_in[86]
  PIN wd_in[87]
    DIRECTION INPUT ;
    USE SIGNAL ;
    PORT
      LAYER M4 ;
      RECT 0.00000 9.31200 0.03600 9.33600 ;
    END
  END wd_in[87]
  PIN wd_in[88]
    DIRECTION INPUT ;
    USE SIGNAL ;
    PORT
      LAYER M4 ;
      RECT 0.00000 9.36000 0.03600 9.38400 ;
    END
  END wd_in[88]
  PIN wd_in[89]
    DIRECTION INPUT ;
    USE SIGNAL ;
    PORT
      LAYER M4 ;
      RECT 0.00000 9.40800 0.03600 9.43200 ;
    END
  END wd_in[89]
  PIN wd_in[90]
    DIRECTION INPUT ;
    USE SIGNAL ;
    PORT
      LAYER M4 ;
      RECT 0.00000 9.45600 0.03600 9.48000 ;
    END
  END wd_in[90]
  PIN wd_in[91]
    DIRECTION INPUT ;
    USE SIGNAL ;
    PORT
      LAYER M4 ;
      RECT 0.00000 9.50400 0.03600 9.52800 ;
    END
  END wd_in[91]
  PIN wd_in[92]
    DIRECTION INPUT ;
    USE SIGNAL ;
    PORT
      LAYER M4 ;
      RECT 0.00000 9.55200 0.03600 9.57600 ;
    END
  END wd_in[92]
  PIN wd_in[93]
    DIRECTION INPUT ;
    USE SIGNAL ;
    PORT
      LAYER M4 ;
      RECT 0.00000 9.60000 0.03600 9.62400 ;
    END
  END wd_in[93]
  PIN wd_in[94]
    DIRECTION INPUT ;
    USE SIGNAL ;
    PORT
      LAYER M4 ;
      RECT 0.00000 9.64800 0.03600 9.67200 ;
    END
  END wd_in[94]
  PIN wd_in[95]
    DIRECTION INPUT ;
    USE SIGNAL ;
    PORT
      LAYER M4 ;
      RECT 0.00000 9.69600 0.03600 9.72000 ;
    END
  END wd_in[95]
  PIN addr_in[0]
    DIRECTION INPUT ;
    USE SIGNAL ;
    PORT
      LAYER M4 ;
      RECT 0.00000 10.22400 0.03600 10.24800 ;
    END
  END addr_in[0]
  PIN addr_in[1]
    DIRECTION INPUT ;
    USE SIGNAL ;
    PORT
      LAYER M4 ;
      RECT 0.00000 10.27200 0.03600 10.29600 ;
    END
  END addr_in[1]
  PIN addr_in[2]
    DIRECTION INPUT ;
    USE SIGNAL ;
    PORT
      LAYER M4 ;
      RECT 0.00000 10.32000 0.03600 10.34400 ;
    END
  END addr_in[2]
  PIN addr_in[3]
    DIRECTION INPUT ;
    USE SIGNAL ;
    PORT
      LAYER M4 ;
      RECT 0.00000 10.36800 0.03600 10.39200 ;
    END
  END addr_in[3]
  PIN addr_in[4]
    DIRECTION INPUT ;
    USE SIGNAL ;
    PORT
      LAYER M4 ;
      RECT 0.00000 10.41600 0.03600 10.44000 ;
    END
  END addr_in[4]
  PIN addr_in[5]
    DIRECTION INPUT ;
    USE SIGNAL ;
    PORT
      LAYER M4 ;
      RECT 0.00000 10.46400 0.03600 10.48800 ;
    END
  END addr_in[5]
  PIN we_in
    DIRECTION INPUT ;
    USE SIGNAL ;
    PORT
      LAYER M4 ;
      RECT 0.00000 10.99200 0.03600 11.01600 ;
    END
  END we_in
  PIN clk
    DIRECTION INPUT ;
    USE SIGNAL ;
    PORT
      LAYER M4 ;
      RECT 0.00000 11.04000 0.03600 11.06400 ;
    END
  END clk
  PIN ce_in
    DIRECTION INPUT ;
    USE SIGNAL ;
    PORT
      LAYER M4 ;
      RECT 0.00000 11.08800 0.03600 11.11200 ;
    END
  END ce_in
  PIN VDD
    DIRECTION INOUT ;
    USE POWER ;
    PORT
      LAYER M4 ;
      RECT 0.09600 0.38400 24.79400 0.48000 ;
      RECT 0.09600 1.15200 24.79400 1.24800 ;
      RECT 0.09600 1.92000 24.79400 2.01600 ;
      RECT 0.09600 2.68800 24.79400 2.78400 ;
      RECT 0.09600 3.45600 24.79400 3.55200 ;
      RECT 0.09600 4.22400 24.79400 4.32000 ;
      RECT 0.09600 4.99200 24.79400 5.08800 ;
      RECT 0.09600 5.76000 24.79400 5.85600 ;
      RECT 0.09600 6.52800 24.79400 6.62400 ;
      RECT 0.09600 7.29600 24.79400 7.39200 ;
      RECT 0.09600 8.06400 24.79400 8.16000 ;
      RECT 0.09600 8.83200 24.79400 8.92800 ;
      RECT 0.09600 9.60000 24.79400 9.69600 ;
      RECT 0.09600 10.36800 24.79400 10.46400 ;
    END
  END VDD
  PIN VSS
    DIRECTION INOUT ;
    USE GROUND ;
    PORT
      LAYER M4 ;
      RECT 0.09600 0.00000 24.79400 0.09600 ;
      RECT 0.09600 0.76800 24.79400 0.86400 ;
      RECT 0.09600 1.53600 24.79400 1.63200 ;
      RECT 0.09600 2.30400 24.79400 2.40000 ;
      RECT 0.09600 3.07200 24.79400 3.16800 ;
      RECT 0.09600 3.84000 24.79400 3.93600 ;
      RECT 0.09600 4.60800 24.79400 4.70400 ;
      RECT 0.09600 5.37600 24.79400 5.47200 ;
      RECT 0.09600 6.14400 24.79400 6.24000 ;
      RECT 0.09600 6.91200 24.79400 7.00800 ;
      RECT 0.09600 7.68000 24.79400 7.77600 ;
      RECT 0.09600 8.44800 24.79400 8.54400 ;
      RECT 0.09600 9.21600 24.79400 9.31200 ;
      RECT 0.09600 9.98400 24.79400 10.08000 ;
      RECT 0.09600 10.75200 24.79400 10.84800 ;
    END
  END VSS
  OBS
    LAYER M1 ;
    RECT 0 0 24.89000 11.20000 ;
    LAYER M2 ;
    RECT 0 0 24.89000 11.20000 ;
    LAYER M3 ;
    RECT 0 0 24.89000 11.20000 ;
    LAYER M4 ;
    RECT 0 0 24.89000 11.20000 ;
  END
END fakeram7_64x96

END LIBRARY
